VERSION 5.8 ;
BUSBITCHARS "[]" ;
DIVIDERCHAR "/" ;

UNITS
    DATABASE MICRONS 1000 ;
END UNITS

# mklef_sram128.py が lef/SRAM128.gds から生成。手で編集しないこと。
# SIZE: 全図形の外形（トップに prBoundary が無い）。GDS の原点はマクロ座標の (82.1, 90.1)。
# ピン: M1PIN(48/1)/M2PIN(49/1) の形状 + TXM1(48/0)/TXM2(49/0) のラベル。
# ピン形状の無いラベル（ピンにしない）: CEp

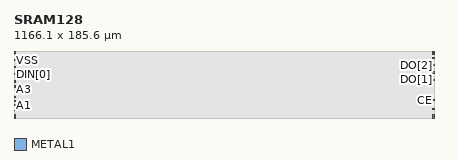
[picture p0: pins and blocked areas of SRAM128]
MACRO SRAM128
    CLASS BLOCK ;
    FOREIGN SRAM128 82.100 90.100 ;
    ORIGIN 0.000 0.000 ;
    SIZE 1166.100 BY 185.600 ;
    SYMMETRY X Y ;

    PIN A0
        DIRECTION INPUT ;
        USE SIGNAL ;
        PORT
            LAYER METAL1 ;
                RECT 0.600 21.400 4.000 24.800 ;
        END
    END A0

    PIN A1
        DIRECTION INPUT ;
        USE SIGNAL ;
        PORT
            LAYER METAL1 ;
                RECT 0.600 33.400 4.000 36.800 ;
        END
    END A1

    PIN A2
        DIRECTION INPUT ;
        USE SIGNAL ;
        PORT
            LAYER METAL1 ;
                RECT 0.600 45.400 4.000 48.800 ;
        END
    END A2

    PIN A3
        DIRECTION INPUT ;
        USE SIGNAL ;
        PORT
            LAYER METAL1 ;
                RECT 0.600 57.400 4.000 60.800 ;
        END
    END A3

    PIN A4
        DIRECTION INPUT ;
        USE SIGNAL ;
        PORT
            LAYER METAL1 ;
                RECT 1162.700 23.400 1166.100 26.800 ;
        END
    END A4

    PIN CE
        DIRECTION INPUT ;
        USE SIGNAL ;
        PORT
            LAYER METAL1 ;
                RECT 1162.700 48.200 1166.100 51.600 ;
        END
    END CE

    PIN DIN[0]
        DIRECTION INPUT ;
        USE SIGNAL ;
        PORT
            LAYER METAL1 ;
                RECT 1.000 99.600 4.400 103.000 ;
        END
    END DIN[0]

    PIN DIN[1]
        DIRECTION INPUT ;
        USE SIGNAL ;
        PORT
            LAYER METAL1 ;
                RECT 1.000 119.600 4.400 123.000 ;
        END
    END DIN[1]

    PIN DIN[2]
        DIRECTION INPUT ;
        USE SIGNAL ;
        PORT
            LAYER METAL1 ;
                RECT 1.000 139.600 4.400 143.000 ;
        END
    END DIN[2]

    PIN DIN[3]
        DIRECTION INPUT ;
        USE SIGNAL ;
        PORT
            LAYER METAL1 ;
                RECT 1.000 159.600 4.400 163.000 ;
        END
    END DIN[3]

    PIN DO[0]
        DIRECTION OUTPUT ;
        USE SIGNAL ;
        PORT
            LAYER METAL1 ;
                RECT 1162.700 104.800 1166.100 108.200 ;
        END
    END DO[0]

    PIN DO[1]
        DIRECTION OUTPUT ;
        USE SIGNAL ;
        PORT
            LAYER METAL1 ;
                RECT 1162.700 124.800 1166.100 128.200 ;
        END
    END DO[1]

    PIN DO[2]
        DIRECTION OUTPUT ;
        USE SIGNAL ;
        PORT
            LAYER METAL1 ;
                RECT 1162.700 144.800 1166.100 148.200 ;
        END
    END DO[2]

    PIN DO[3]
        DIRECTION OUTPUT ;
        USE SIGNAL ;
        PORT
            LAYER METAL1 ;
                RECT 1162.700 164.800 1166.100 168.200 ;
        END
    END DO[3]

    PIN WR
        DIRECTION INPUT ;
        USE SIGNAL ;
        PORT
            LAYER METAL1 ;
                RECT 1.000 85.600 4.400 89.000 ;
        END
    END WR

    PIN VDD
        DIRECTION INOUT ;
        USE POWER ;
        SHAPE ABUTMENT ;
        PORT
            LAYER METAL1 ;
                RECT 0.000 5.400 3.400 8.800 ;
            LAYER METAL1 ;
                RECT 0.000 176.800 3.400 180.200 ;
            LAYER METAL1 ;
                RECT 1162.700 5.400 1166.100 8.800 ;
            LAYER METAL1 ;
                RECT 1162.700 176.800 1166.100 180.200 ;
        END
    END VDD

    PIN VSS
        DIRECTION INOUT ;
        USE GROUND ;
        SHAPE ABUTMENT ;
        PORT
            LAYER METAL1 ;
                RECT 0.000 0.000 3.400 3.400 ;
            LAYER METAL1 ;
                RECT 0.000 182.200 3.400 185.600 ;
            LAYER METAL1 ;
                RECT 1162.700 0.000 1166.100 3.400 ;
            LAYER METAL1 ;
                RECT 1162.700 182.200 1166.100 185.600 ;
        END
    END VSS

    OBS
        LAYER METAL1 ;
            RECT 6.000 0.000 1160.000 185.600 ;
            RECT 3.400 -0.000 10.000 3.400 ;
            RECT 1156.000 -0.000 1162.700 3.400 ;
            RECT 3.400 5.400 10.000 8.800 ;
            RECT 1156.000 5.400 1162.700 8.800 ;
            RECT 5.800 12.600 9.200 14.200 ;
            RECT 5.800 14.200 10.000 16.000 ;
            RECT 6.100 17.800 10.000 19.600 ;
            RECT 6.100 19.600 8.700 20.400 ;
            RECT 1.000 18.600 3.600 21.400 ;
            RECT 1156.000 19.800 1158.700 21.600 ;
            RECT 1156.100 21.600 1158.700 22.400 ;
            RECT 6.100 21.800 10.000 24.400 ;
            RECT 1156.000 23.800 1158.700 26.400 ;
            RECT 6.100 25.800 8.700 26.600 ;
            RECT 6.100 26.600 10.000 28.400 ;
            RECT 1162.700 26.800 1165.700 27.000 ;
            RECT 1160.800 27.000 1165.700 29.600 ;
            RECT 1156.100 27.800 1158.700 28.600 ;
            RECT 1156.000 28.600 1158.700 30.400 ;
            RECT 6.100 29.800 10.000 31.600 ;
            RECT 6.100 31.600 8.700 32.400 ;
            RECT 1.000 30.600 3.600 33.400 ;
            RECT 1156.000 31.800 1158.700 33.600 ;
            RECT 1156.100 33.600 1158.700 34.400 ;
            RECT 6.100 33.800 10.000 36.400 ;
            RECT 1156.000 35.800 1158.700 38.400 ;
            RECT 6.100 37.800 8.700 38.600 ;
            RECT 6.100 38.600 10.000 40.400 ;
            RECT 1156.100 39.800 1158.700 40.600 ;
            RECT 1156.000 40.600 1158.700 42.400 ;
            RECT 6.100 41.800 10.000 43.600 ;
            RECT 6.100 43.600 8.700 44.400 ;
            RECT 1.000 42.600 3.600 45.400 ;
            RECT 1156.000 45.200 1158.700 47.800 ;
            RECT 6.100 45.800 10.000 48.400 ;
            RECT 6.100 49.800 8.700 50.600 ;
            RECT 6.100 50.600 10.000 52.400 ;
            RECT 1156.000 50.600 1158.700 52.400 ;
            RECT 1156.100 52.400 1158.700 53.200 ;
            RECT 1160.100 48.200 1162.700 54.200 ;
            RECT 6.100 53.800 10.000 55.600 ;
            RECT 6.100 55.600 8.700 56.400 ;
            RECT 1.000 54.600 3.600 57.400 ;
            RECT 1156.100 54.600 1158.700 55.600 ;
            RECT 1156.000 55.600 1164.500 58.200 ;
            RECT 1156.100 58.200 1158.700 59.200 ;
            RECT 6.100 57.800 10.000 60.400 ;
            RECT 1156.000 61.600 1158.700 63.400 ;
            RECT 1156.100 63.400 1158.700 64.200 ;
            RECT 6.100 61.800 8.700 62.600 ;
            RECT 6.100 62.600 10.000 64.400 ;
            RECT 6.100 65.800 10.000 67.600 ;
            RECT 6.100 67.600 8.700 68.400 ;
            RECT 1156.000 69.600 1158.700 72.200 ;
            RECT 6.100 69.800 10.000 72.400 ;
            RECT 1.400 66.600 4.000 69.400 ;
            RECT 1.000 69.400 4.400 72.800 ;
            RECT 6.100 73.800 8.700 74.600 ;
            RECT 6.100 74.600 10.000 76.400 ;
            RECT 1156.100 74.600 1158.700 75.600 ;
            RECT 1156.000 75.600 1164.500 78.200 ;
            RECT 1156.100 78.200 1158.700 79.200 ;
            RECT 6.100 77.800 8.700 78.200 ;
            RECT 6.100 78.200 10.000 80.000 ;
            RECT 6.100 80.000 8.700 80.400 ;
            RECT 1156.100 80.600 1158.700 81.000 ;
            RECT 1156.000 81.000 1158.700 82.800 ;
            RECT 1156.100 82.800 1158.700 83.200 ;
            RECT 1.400 82.800 4.000 85.600 ;
            RECT 1160.100 83.400 1162.700 86.000 ;
            RECT 6.100 84.000 8.700 85.400 ;
            RECT 6.100 85.400 10.000 88.400 ;
            RECT 1.800 89.000 4.400 90.200 ;
            RECT 1.800 90.200 10.000 92.000 ;
            RECT 1156.100 84.600 1158.700 86.200 ;
            RECT 1156.000 86.200 1158.700 94.600 ;
            RECT 9.400 95.400 10.000 96.000 ;
            RECT 6.100 96.000 10.000 98.000 ;
            RECT 6.100 98.000 10.000 98.600 ;
            RECT 1156.000 96.000 1158.700 97.800 ;
            RECT 1156.100 97.800 1158.700 98.600 ;
            RECT 6.100 100.000 10.000 102.600 ;
            RECT 1156.000 100.000 1164.500 102.600 ;
            RECT 1.000 103.000 3.600 105.800 ;
            RECT 1156.100 104.000 1158.700 104.800 ;
            RECT 1156.000 104.800 1162.700 106.600 ;
            RECT 6.100 104.000 10.000 104.600 ;
            RECT 6.100 104.600 10.000 106.600 ;
            RECT 9.400 106.600 10.000 107.200 ;
            RECT 1156.000 108.000 1158.700 114.600 ;
            RECT 9.400 115.400 10.000 116.000 ;
            RECT 6.100 116.000 10.000 118.000 ;
            RECT 6.100 118.000 10.000 118.600 ;
            RECT 1156.000 116.000 1158.700 117.800 ;
            RECT 1156.100 117.800 1158.700 118.600 ;
            RECT 6.100 120.000 10.000 122.600 ;
            RECT 1156.000 120.000 1164.500 122.600 ;
            RECT 1.000 123.000 3.600 125.800 ;
            RECT 1156.100 124.000 1158.700 124.800 ;
            RECT 1156.000 124.800 1162.700 126.600 ;
            RECT 6.100 124.000 10.000 124.600 ;
            RECT 6.100 124.600 10.000 126.600 ;
            RECT 9.400 126.600 10.000 127.200 ;
            RECT 1156.000 128.000 1158.700 134.600 ;
            RECT 9.400 135.400 10.000 136.000 ;
            RECT 6.100 136.000 10.000 138.000 ;
            RECT 6.100 138.000 10.000 138.600 ;
            RECT 1156.000 136.000 1158.700 137.800 ;
            RECT 1156.100 137.800 1158.700 138.600 ;
            RECT 6.100 140.000 10.000 142.600 ;
            RECT 1156.000 140.000 1164.500 142.600 ;
            RECT 1.000 143.000 3.600 145.800 ;
            RECT 1156.100 144.000 1158.700 144.800 ;
            RECT 1156.000 144.800 1162.700 146.600 ;
            RECT 6.100 144.000 10.000 144.600 ;
            RECT 6.100 144.600 10.000 146.600 ;
            RECT 9.400 146.600 10.000 147.200 ;
            RECT 1156.000 148.000 1158.700 154.600 ;
            RECT 9.400 155.400 10.000 156.000 ;
            RECT 6.100 156.000 10.000 158.000 ;
            RECT 6.100 158.000 10.000 158.600 ;
            RECT 1156.000 156.000 1158.700 157.800 ;
            RECT 1156.100 157.800 1158.700 158.600 ;
            RECT 6.100 160.000 10.000 162.600 ;
            RECT 1156.000 160.000 1164.500 162.600 ;
            RECT 1.000 163.000 3.600 165.800 ;
            RECT 1156.100 164.000 1158.700 164.800 ;
            RECT 1156.000 164.800 1162.700 166.600 ;
            RECT 6.100 164.000 10.000 164.600 ;
            RECT 6.100 164.600 10.000 166.600 ;
            RECT 9.400 166.600 10.000 167.200 ;
            RECT 1156.000 168.000 1158.700 173.000 ;
            RECT 3.400 176.800 10.000 180.200 ;
            RECT 1156.000 176.800 1162.700 180.200 ;
            RECT 3.400 182.200 10.000 185.600 ;
            RECT 1156.000 182.200 1162.700 185.600 ;
        LAYER VIA1 ;
            RECT 0.000 0.000 1166.100 185.600 ;
        LAYER METAL2 ;
            RECT 0.000 0.000 1166.100 185.600 ;
    END
END SRAM128

END LIBRARY
